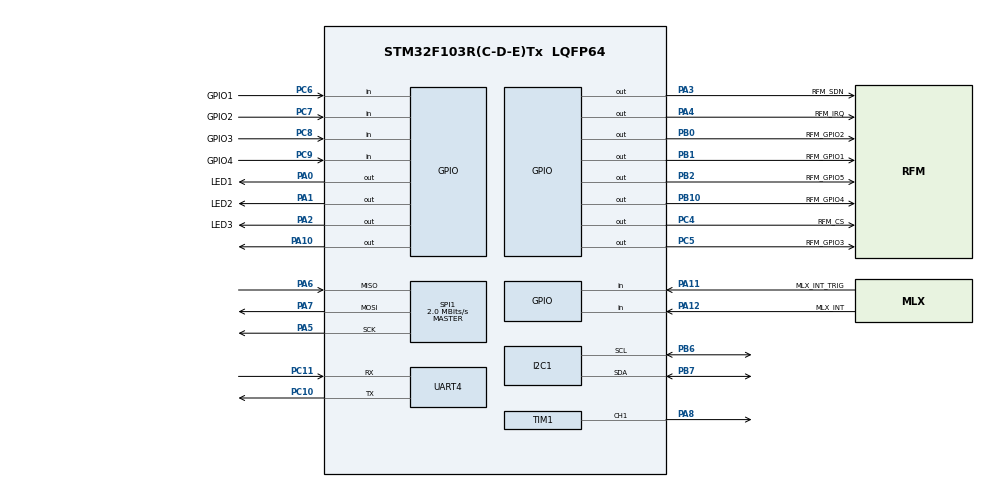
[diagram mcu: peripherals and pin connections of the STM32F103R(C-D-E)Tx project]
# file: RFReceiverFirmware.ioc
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Mcu.Family=STM32F1
Mcu.Name=STM32F103R(C-D-E)Tx
Mcu.Package=LQFP64
NVIC.PriorityGroup=NVIC_PRIORITYGROUP_4
NVIC.TIM2_IRQn=true\:0\:0\:false\:false\:true\:true\:true\:true
NVIC.TIM3_IRQn=true\:0\:0\:false\:false\:true\:true\:true\:true
NVIC.TIM4_IRQn=true\:0\:0\:false\:false\:true\:true\:true\:true
NVIC.TIM5_IRQn=true\:0\:0\:false\:false\:true\:true\:true\:true
PA0-WKUP.GPIO_Label=LED1
PA0-WKUP.Signal=GPIO_Output
PA1.GPIO_Label=LED2
PA1.Signal=GPIO_Output
PA10.Signal=GPIO_Output
PA11.GPIO_Label=MLX_INT_TRIG
PA11.Signal=GPIO_Input
PA12.GPIO_Label=MLX_INT
PA12.Signal=GPIO_Input
PA13.Mode=Trace_Asynchronous_SW
PA13.Signal=SYS_JTMS-SWDIO
PA14.Mode=Trace_Asynchronous_SW
PA14.Signal=SYS_JTCK-SWCLK
PA2.GPIO_Label=LED3
PA2.Signal=GPIO_Output
PA3.GPIO_Label=RFM_SDN
PA3.Signal=GPIO_Output
PA4.GPIO_Label=RFM_IRQ
PA4.Signal=GPIO_Output
PA5.Mode=Full_Duplex_Master
PA5.Signal=SPI1_SCK
PA6.Mode=Full_Duplex_Master
PA6.Signal=SPI1_MISO
PA7.Mode=Full_Duplex_Master
PA7.Signal=SPI1_MOSI
PA8.Signal=S_TIM1_CH1
PB0.GPIO_Label=RFM_GPIO2
PB0.Signal=GPIO_Output
PB1.GPIO_Label=RFM_GPIO1
PB1.Signal=GPIO_Output
PB10.GPIO_Label=RFM_GPIO4
PB10.Signal=GPIO_Output
PB2.GPIO_Label=RFM_GPIO5
PB2.Signal=GPIO_Output
PB3.Mode=Trace_Asynchronous_SW
PB3.Signal=SYS_JTDO-TRACESWO
PB6.Mode=I2C
PB6.Signal=I2C1_SCL
PB7.Mode=I2C
PB7.Signal=I2C1_SDA
PC10.Mode=Asynchronous
PC10.Signal=UART4_TX
PC11.Mode=Asynchronous
PC11.Signal=UART4_RX
PC4.GPIO_Label=RFM_CS
PC4.Signal=GPIO_Output
PC5.GPIO_Label=RFM_GPIO3
PC5.Signal=GPIO_Output
PC6.GPIO_Label=GPIO1
PC6.Signal=GPIO_Input
PC7.GPIO_Label=GPIO2
PC7.Signal=GPIO_Input
PC8.GPIO_Label=GPIO3
PC8.Signal=GPIO_Input
PC9.GPIO_Label=GPIO4
PC9.Signal=GPIO_Input
ProjectManager.HeapSize=0x200
ProjectManager.StackSize=0x400
ProjectManager.TargetToolchain=STM32CubeIDE
RCC.AHBFreq_Value=64000000
RCC.APB1CLKDivider=RCC_HCLK_DIV2
RCC.APB1Freq_Value=32000000
RCC.APB1TimFreq_Value=64000000
RCC.APB2Freq_Value=64000000
RCC.APB2TimFreq_Value=64000000
RCC.HCLKFreq_Value=64000000
RCC.PLLMUL=RCC_PLL_MUL16
RCC.SYSCLKFreq_VALUE=64000000
RCC.SYSCLKSource=RCC_SYSCLKSOURCE_PLLCLK
RCC.USBFreq_Value=64000000
SH.S_TIM1_CH1.0=TIM1_CH1,PWM Generation1 CH1
SPI1.BaudRatePrescaler=SPI_BAUDRATEPRESCALER_32
SPI1.CalculateBaudRate=2.0 MBits/s
SPI1.Direction=SPI_DIRECTION_2LINES
SPI1.Mode=SPI_MODE_MASTER
SPI1.VirtualType=VM_MASTER
TIM1.Channel-PWM\ Generation1\ CH1=TIM_CHANNEL_1
TIM1.Prescaler=900
TIM1.TIM_MasterOutputTrigger=TIM_TRGO_OC1REF
TIM2.Channel-Output\ Compare1\ No\ Output=TIM_CHANNEL_1
TIM2.OCMode_1=TIM_OCMODE_ACTIVE
TIM2.Prescaler=64000
TIM3.Channel-Output\ Compare1\ No\ Output=TIM_CHANNEL_1
TIM3.OCMode_1=TIM_OCMODE_ACTIVE
TIM3.Prescaler=16000
TIM4.Channel-Output\ Compare1\ No\ Output=TIM_CHANNEL_1
TIM4.OCMode_1=TIM_OCMODE_ACTIVE
TIM4.Prescaler=16000
TIM5.Channel-Output\ Compare1\ No\ Output=TIM_CHANNEL_1
TIM5.OCMode_1=TIM_OCMODE_ACTIVE
TIM5.Prescaler=64000
UART4.VirtualMode=Asynchronous
VP_TIM1_VS_ClockSourceINT.Mode=Internal
VP_TIM2_VS_ClockSourceINT.Mode=Internal
VP_TIM2_VS_no_output1.Mode=Output Compare1 No Output
VP_TIM3_VS_ClockSourceINT.Mode=Internal
VP_TIM3_VS_no_output1.Mode=Output Compare1 No Output
VP_TIM4_VS_ClockSourceINT.Mode=Internal
VP_TIM4_VS_no_output1.Mode=Output Compare1 No Output
VP_TIM5_VS_ClockSourceINT.Mode=Internal
VP_TIM5_VS_no_output1.Mode=Output Compare1 No Output
board=custom

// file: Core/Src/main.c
/* USER CODE BEGIN Header */
/**
  ******************************************************************************
  * @file           : main.c
  * @brief          : Main program body
  ******************************************************************************
  * @attention
  *
  * Copyright (c) 2025 STMicroelectronics.
  * All rights reserved.
  *
  * This software is licensed under terms that can be found in the LICENSE file
  * in the root directory of this software component.
  * If no LICENSE file comes with this software, it is provided AS-IS.
  *
  ******************************************************************************
  */
#include "GAUL_drivers/RFM22.h"
#include "GAUL_drivers/Pulse_pin.h"
#include "GAUL_drivers/i2c_lcd.h"
#include "GAUL_drivers/buzzer.h"
#include "stdio.h"
#include <string.h>
/* USER CODE END Header */
#include "main.h"

I2C_HandleTypeDef hi2c1;

SPI_HandleTypeDef hspi1;

TIM_HandleTypeDef htim1;
TIM_HandleTypeDef htim2;
TIM_HandleTypeDef htim3;
TIM_HandleTypeDef htim4;
TIM_HandleTypeDef htim5;

UART_HandleTypeDef huart4;

void SystemClock_Config(void);
static void MX_GPIO_Init(void);
static void MX_I2C1_Init(void);
static void MX_SPI1_Init(void);
static void MX_TIM1_Init(void);
static void MX_TIM2_Init(void);
static void MX_TIM3_Init(void);
static void MX_TIM4_Init(void);
static void MX_TIM5_Init(void);
static void MX_UART4_Init(void);
/* USER CODE BEGIN PFP */
void PUSH_ISR(uint16_t GPIO_pin);
/* USER CODE END PFP */

/* USER CODE BEGIN 0 */

uint8_t rfm22_interrupt_flag = 0;
uint8_t pushbutton_interrupt_flag = 0;
uint8_t pushbutton_pushed[4] = {0};

void HAL_GPIO_EXTI_Callback(uint16_t GPIO_Pin)
{
	if (GPIO_Pin == RFM_IRQ_Pin) rfm22_interrupt_flag = 1;
	if ((GPIO_Pin == GPIO1_Pin) | (GPIO_Pin == GPIO2_Pin) | (GPIO_Pin == GPIO3_Pin) | (GPIO_Pin == GPIO4_Pin)) PUSH_ISR(GPIO_Pin);
}

void PUSH_ISR(uint16_t GPIO_pin)
{
	pushbutton_interrupt_flag = 1;
	pushbutton_pushed[0] |= (GPIO_pin == GPIO1_Pin);
	pushbutton_pushed[1] |= (GPIO_pin == GPIO2_Pin);
	pushbutton_pushed[2] |= (GPIO_pin == GPIO3_Pin);
	pushbutton_pushed[3] |= (GPIO_pin == GPIO4_Pin);

}

void signal_strenght_bar(char *string, int length, float percent)
{
	if (percent > 100) percent = 100;
	int nb_square = percent * length / 100;
	int nb_dash = length - nb_square;

	for (int i = 0; i < nb_square; i++)
	{
		string[i] = '#';
	}
	for (int i = nb_square; i < length; i++)
	{
		string[i] = '-';
	}
}

void print_menu(RFM22 *dev, I2C_LCD_HandleTypeDef *lcd, uint8_t channel, uint8_t rssi, uint8_t ref_rssi, float latitude, float longitude)
{
	char line[20] = {'-'};
	uint32_t freq = RFM22_get_frequency(dev);
	uint16_t MHz = freq /1e6;
	uint16_t kHz = (freq/1000) % 1000;
	uint16_t Hz = freq % 1000;

	float signal_strenght = 100*((float)rssi-(float)ref_rssi)/((float)ref_rssi+1) + 50;

	lcd_clear(lcd);
	lcd_gotoxy(lcd, 0, 0); // ligne 1
	snprintf(line, 21, "CH:%-3u   %3lu.%03lu.%03lu", channel, MHz, kHz, Hz);
	lcd_puts(lcd, line);
	lcd_gotoxy(lcd, 0, 1); // ligne 2
	snprintf(line, 20, "RSSI:%u", rssi);
	lcd_puts(lcd, line);
	lcd_gotoxy(lcd, 0, 2); // ligne 3
	strcpy(line, "GPS");
	lcd_puts(lcd, line);
	lcd_gotoxy(lcd, 0, 3); // ligne 4
	signal_strenght_bar(line, 20, signal_strenght);
	lcd_puts(lcd, line);

}

/* USER CODE END 0 */

int main(void)
{

  /* MCU Configuration--------------------------------------------------------*/

  /* Reset of all peripherals, Initializes the Flash interface and the Systick. */
  HAL_Init();

  /* Configure the system clock */
  SystemClock_Config();

  /* Initialize all configured peripherals */
  MX_GPIO_Init();
  MX_I2C1_Init();
  MX_SPI1_Init();
  MX_TIM1_Init();
  MX_TIM2_Init();
  MX_TIM3_Init();
  MX_TIM4_Init();
  MX_TIM5_Init();
  MX_UART4_Init();
  /* USER CODE BEGIN 2 */
  // init pulsed pins and their respective timers
  Pulse_Pin_Typedef pin1 = PulsePin_init(LED1_GPIO_Port, LED1_Pin, &htim2, TIM_CHANNEL_1);
  Pulse_Pin_Typedef pin2 = PulsePin_init(LED2_GPIO_Port, LED2_Pin, &htim3, TIM_CHANNEL_1);
  Pulse_Pin_Typedef pin3 = PulsePin_init(LED3_GPIO_Port, LED3_Pin, &htim4, TIM_CHANNEL_1);

  // init buzzer and its watch timer
  buzzer_init(&htim1, TIM_CHANNEL_3, &htim5, TIM_CHANNEL_1);

  // init lcd
  I2C_LCD_HandleTypeDef lcd;
  lcd.hi2c = &hi2c1;
  lcd.address = 0x27<<1;
  lcd_init(&lcd);
  lcd_clear(&lcd);

  //init rfm22
  RFM22 rfm22 = {
		  .SPIx = &hspi1,
		  .cs_port = RFM_CS_GPIO_Port,
		  .cs_pin = RFM_CS_Pin,
		  .snd_port = RFM_SDN_GPIO_Port,
		  .snd_pin = RFM_SDN_Pin,
		  .nirq_port = RFM_IRQ_GPIO_Port,
		  .nirq_pin = RFM_IRQ_Pin,
		  .gpio_port_1 = RFM_GPIO1_GPIO_Port,
		  .gpio_pin_1 = RFM_GPIO1_Pin,
		  .gpio_port_2 = RFM_GPIO2_GPIO_Port,
		  .gpio_pin_2 = RFM_GPIO2_Pin,
		  .gpio_port_3 = RFM_GPIO3_GPIO_Port,
		  .gpio_pin_3 = RFM_GPIO3_Pin
  };

  RFM22_init(&rfm22, &rfm22_confs);
  uint8_t channel = 0;
  /* USER CODE END 2 */

  /* Infinite loop */
  /* USER CODE BEGIN WHILE */

  //global vars
  RFM22_channel(&rfm22, channel);
  print_menu(&rfm22, &lcd, 0, 0, 0, 0, 0);
  const char* packet_str = "VE2VQW";
  uint8_t packet[8];
  memcpy(packet,packet_str, 6);    // copy packet_str to packet without '\0'
  uint8_t rssi = 0;
  uint8_t ref_rssi = 0;
  uint32_t freq;
  float latitude = 0;
  float longitude = 0;
  uint8_t spi_rx[1] = {0};

  while (1)
  {
    /* USER CODE END WHILE */

    /* USER CODE BEGIN 3 */

#ifdef TRANSMIT
	  RFM22_transmit(&rfm22, packet, 8);
	  uint32_t tick = HAL_GetTick();
	  while (HAL_GetTick() - tick < 1000);
#endif

#ifdef RECEIVE
	  RFM22_SPI_read(&rfm22, RH_RF22_REG_07_OPERATING_MODE1, spi_rx, 1);
	  if (!(spi_rx[0] & RH_RF22_RXON))
	  {
		  RFM22_rx_mode(&rfm22);
      }
#endif

	  //handle rfm22 interrupts
	  if (rfm22_interrupt_flag || (!HAL_GPIO_ReadPin(RFM_IRQ_GPIO_Port, RFM_IRQ_Pin)))
#ifdef TRANSMIT
	  {
		  rfm22_interrupt_flag = 0;
		  uint8_t interrupts[] = {0, 0};
		  RFM22_SPI_read(&rfm22, RH_RF22_REG_03_INTERRUPT_STATUS1, interrupts, 2);

		  //pk sent interrupt
		  if (interrupts[0] & RH_RF22_IPKSENT)
		  {
			  PulsePin(pin1, 100);
		  }

		  //tx FIFO full
		  if (interrupts[0 & RH_RF22_ITXFFAFULL])
		  {
			  RFM22_clr_tx_FIFO(&rfm22);
		  }
	  }
#endif

#ifdef RECEIVE
	  {
		  rfm22_interrupt_flag = 0;
		  uint8_t interrupts[] = {0, 0};
		  RFM22_SPI_read(&rfm22, RH_RF22_REG_03_INTERRUPT_STATUS1, interrupts, 2);

		  //pk received
		  if (interrupts[0] & RH_RF22_IPKVALID)
		  {
			  PulsePin(pin1, 100);
			  uint8_t lenght = RFM22_available(&rfm22);

			  // GPS routine
			  rssi = RFM22_get_RSSI(&rfm22);
			  RFM22_read_rx(&rfm22, packet, 8);
			  latitude = 0; // à vérifier, supposé transformer en float direct
			  longitude = 0;

			  // rssi routine
			  int16_t rssi_dif = rssi - ref_rssi;
			  freq = 3000 + 200*rssi_dif;
			  buzzer_start(freq, 200);
			  print_menu(&rfm22, &lcd, channel, rssi, ref_rssi, latitude, longitude);
		  }

		  //rx FIFO full
		  if (interrupts[0] & RH_RF22_IRXFFAFULL)
		  {
			  //read last received
			  //RFM22_clr_rx_FIFO(&rfm22);
			  PulsePin(pin3, 100);
		  }

		  //valid preamble
		  if (interrupts[1] & RH_RF22_IPREAVAL)
		  {
		  }

		  //inval preamble
		  if (interrupts[1] & RH_RF22_IPREAINVAL)
		  {
			  PulsePin(pin2, 100);
		  }
	  }

	  if (pushbutton_interrupt_flag)
	  {
		  pushbutton_interrupt_flag = 0;

		  if (pushbutton_pushed[0]) // channel up
		  {
			  channel++;
			  RFM22_channel(&rfm22, channel);
			  print_menu(&rfm22, &lcd, channel, rssi, ref_rssi, latitude, longitude);
		  }
		  if (pushbutton_pushed[1]) // channel down
		  {
			  channel--;
			  RFM22_channel(&rfm22, channel);
			  print_menu(&rfm22, &lcd, channel, rssi, ref_rssi, latitude, longitude);
		  }
		  if (pushbutton_pushed[2]) // zero
		  {
			  ref_rssi = rssi;
		  }
		  if (pushbutton_pushed[3])
		  {

		  }

		  pushbutton_pushed[0] = 0;
		  pushbutton_pushed[1] = 0;
		  pushbutton_pushed[2] = 0;
		  pushbutton_pushed[3] = 0;
	  }
#endif
  }
  /* USER CODE END 3 */
}

void SystemClock_Config(void)
{
  RCC_OscInitTypeDef RCC_OscInitStruct = {0};
  RCC_ClkInitTypeDef RCC_ClkInitStruct = {0};

  /** Initializes the RCC Oscillators according to the specified parameters
  * in the RCC_OscInitTypeDef structure.
  */
  RCC_OscInitStruct.OscillatorType = RCC_OSCILLATORTYPE_HSE;
  RCC_OscInitStruct.HSEState = RCC_HSE_ON;
  RCC_OscInitStruct.HSEPredivValue = RCC_HSE_PREDIV_DIV1;
  RCC_OscInitStruct.HSIState = RCC_HSI_ON;
  RCC_OscInitStruct.PLL.PLLState = RCC_PLL_ON;
  RCC_OscInitStruct.PLL.PLLSource = RCC_PLLSOURCE_HSE;
  RCC_OscInitStruct.PLL.PLLMUL = RCC_PLL_MUL9;
  if (HAL_RCC_OscConfig(&RCC_OscInitStruct) != HAL_OK)
  {
    Error_Handler();
  }

  /** Initializes the CPU, AHB and APB buses clocks
  */
  RCC_ClkInitStruct.ClockType = RCC_CLOCKTYPE_HCLK|RCC_CLOCKTYPE_SYSCLK
                              |RCC_CLOCKTYPE_PCLK1|RCC_CLOCKTYPE_PCLK2;
  RCC_ClkInitStruct.SYSCLKSource = RCC_SYSCLKSOURCE_PLLCLK;
  RCC_ClkInitStruct.AHBCLKDivider = RCC_SYSCLK_DIV1;
  RCC_ClkInitStruct.APB1CLKDivider = RCC_HCLK_DIV2;
  RCC_ClkInitStruct.APB2CLKDivider = RCC_HCLK_DIV1;

  if (HAL_RCC_ClockConfig(&RCC_ClkInitStruct, FLASH_LATENCY_2) != HAL_OK)
  {
    Error_Handler();
  }
}

static void MX_I2C1_Init(void)
{

  hi2c1.Instance = I2C1;
  hi2c1.Init.ClockSpeed = 100000;
  hi2c1.Init.DutyCycle = I2C_DUTYCYCLE_2;
  hi2c1.Init.OwnAddress1 = 0;
  hi2c1.Init.AddressingMode = I2C_ADDRESSINGMODE_7BIT;
  hi2c1.Init.DualAddressMode = I2C_DUALADDRESS_DISABLE;
  hi2c1.Init.OwnAddress2 = 0;
  hi2c1.Init.GeneralCallMode = I2C_GENERALCALL_DISABLE;
  hi2c1.Init.NoStretchMode = I2C_NOSTRETCH_DISABLE;
  if (HAL_I2C_Init(&hi2c1) != HAL_OK)
  {
    Error_Handler();
  }

}

static void MX_SPI1_Init(void)
{

  /* SPI1 parameter configuration*/
  hspi1.Instance = SPI1;
  hspi1.Init.Mode = SPI_MODE_MASTER;
  hspi1.Init.Direction = SPI_DIRECTION_2LINES;
  hspi1.Init.DataSize = SPI_DATASIZE_8BIT;
  hspi1.Init.CLKPolarity = SPI_POLARITY_LOW;
  hspi1.Init.CLKPhase = SPI_PHASE_1EDGE;
  hspi1.Init.NSS = SPI_NSS_SOFT;
  hspi1.Init.BaudRatePrescaler = SPI_BAUDRATEPRESCALER_32;
  hspi1.Init.FirstBit = SPI_FIRSTBIT_MSB;
  hspi1.Init.TIMode = SPI_TIMODE_DISABLE;
  hspi1.Init.CRCCalculation = SPI_CRCCALCULATION_DISABLE;
  hspi1.Init.CRCPolynomial = 10;
  if (HAL_SPI_Init(&hspi1) != HAL_OK)
  {
    Error_Handler();
  }

}

static void MX_TIM1_Init(void)
{

  TIM_ClockConfigTypeDef sClockSourceConfig = {0};
  TIM_MasterConfigTypeDef sMasterConfig = {0};
  TIM_OC_InitTypeDef sConfigOC = {0};
  TIM_BreakDeadTimeConfigTypeDef sBreakDeadTimeConfig = {0};

  htim1.Instance = TIM1;
  htim1.Init.Prescaler = 900;
  htim1.Init.CounterMode = TIM_COUNTERMODE_UP;
  htim1.Init.Period = 65535;
  htim1.Init.ClockDivision = TIM_CLOCKDIVISION_DIV1;
  htim1.Init.RepetitionCounter = 0;
  htim1.Init.AutoReloadPreload = TIM_AUTORELOAD_PRELOAD_DISABLE;
  if (HAL_TIM_Base_Init(&htim1) != HAL_OK)
  {
    Error_Handler();
  }
  sClockSourceConfig.ClockSource = TIM_CLOCKSOURCE_INTERNAL;
  if (HAL_TIM_ConfigClockSource(&htim1, &sClockSourceConfig) != HAL_OK)
  {
    Error_Handler();
  }
  if (HAL_TIM_PWM_Init(&htim1) != HAL_OK)
  {
    Error_Handler();
  }
  sMasterConfig.MasterOutputTrigger = TIM_TRGO_OC1REF;
  sMasterConfig.MasterSlaveMode = TIM_MASTERSLAVEMODE_DISABLE;
  if (HAL_TIMEx_MasterConfigSynchronization(&htim1, &sMasterConfig) != HAL_OK)
  {
    Error_Handler();
  }
  sConfigOC.OCMode = TIM_OCMODE_PWM1;
  sConfigOC.Pulse = 0;
  sConfigOC.OCPolarity = TIM_OCPOLARITY_HIGH;
  sConfigOC.OCNPolarity = TIM_OCNPOLARITY_HIGH;
  sConfigOC.OCFastMode = TIM_OCFAST_DISABLE;
  sConfigOC.OCIdleState = TIM_OCIDLESTATE_RESET;
  sConfigOC.OCNIdleState = TIM_OCNIDLESTATE_RESET;
  if (HAL_TIM_PWM_ConfigChannel(&htim1, &sConfigOC, TIM_CHANNEL_3) != HAL_OK)
  {
    Error_Handler();
  }
  sBreakDeadTimeConfig.OffStateRunMode = TIM_OSSR_DISABLE;
  sBreakDeadTimeConfig.OffStateIDLEMode = TIM_OSSI_DISABLE;
  sBreakDeadTimeConfig.LockLevel = TIM_LOCKLEVEL_OFF;
  sBreakDeadTimeConfig.DeadTime = 0;
  sBreakDeadTimeConfig.BreakState = TIM_BREAK_DISABLE;
  sBreakDeadTimeConfig.BreakPolarity = TIM_BREAKPOLARITY_HIGH;
  sBreakDeadTimeConfig.AutomaticOutput = TIM_AUTOMATICOUTPUT_DISABLE;
  if (HAL_TIMEx_ConfigBreakDeadTime(&htim1, &sBreakDeadTimeConfig) != HAL_OK)
  {
    Error_Handler();
  }
  HAL_TIM_MspPostInit(&htim1);

}

static void MX_TIM2_Init(void)
{

  TIM_ClockConfigTypeDef sClockSourceConfig = {0};
  TIM_MasterConfigTypeDef sMasterConfig = {0};
  TIM_OC_InitTypeDef sConfigOC = {0};

  htim2.Instance = TIM2;
  htim2.Init.Prescaler = 64000;
  htim2.Init.CounterMode = TIM_COUNTERMODE_UP;
  htim2.Init.Period = 65535;
  htim2.Init.ClockDivision = TIM_CLOCKDIVISION_DIV1;
  htim2.Init.AutoReloadPreload = TIM_AUTORELOAD_PRELOAD_DISABLE;
  if (HAL_TIM_Base_Init(&htim2) != HAL_OK)
  {
    Error_Handler();
  }
  sClockSourceConfig.ClockSource = TIM_CLOCKSOURCE_INTERNAL;
  if (HAL_TIM_ConfigClockSource(&htim2, &sClockSourceConfig) != HAL_OK)
  {
    Error_Handler();
  }
  if (HAL_TIM_OC_Init(&htim2) != HAL_OK)
  {
    Error_Handler();
  }
  sMasterConfig.MasterOutputTrigger = TIM_TRGO_RESET;
  sMasterConfig.MasterSlaveMode = TIM_MASTERSLAVEMODE_DISABLE;
  if (HAL_TIMEx_MasterConfigSynchronization(&htim2, &sMasterConfig) != HAL_OK)
  {
    Error_Handler();
  }
  sConfigOC.OCMode = TIM_OCMODE_ACTIVE;
  sConfigOC.Pulse = 0;
  sConfigOC.OCPolarity = TIM_OCPOLARITY_HIGH;
  sConfigOC.OCFastMode = TIM_OCFAST_DISABLE;
  if (HAL_TIM_OC_ConfigChannel(&htim2, &sConfigOC, TIM_CHANNEL_1) != HAL_OK)
  {
    Error_Handler();
  }

}

static void MX_TIM3_Init(void)
{

  TIM_ClockConfigTypeDef sClockSourceConfig = {0};
  TIM_MasterConfigTypeDef sMasterConfig = {0};
  TIM_OC_InitTypeDef sConfigOC = {0};

  htim3.Instance = TIM3;
  htim3.Init.Prescaler = 16000;
  htim3.Init.CounterMode = TIM_COUNTERMODE_UP;
  htim3.Init.Period = 65535;
  htim3.Init.ClockDivision = TIM_CLOCKDIVISION_DIV1;
  htim3.Init.AutoReloadPreload = TIM_AUTORELOAD_PRELOAD_DISABLE;
  if (HAL_TIM_Base_Init(&htim3) != HAL_OK)
  {
    Error_Handler();
  }
  sClockSourceConfig.ClockSource = TIM_CLOCKSOURCE_INTERNAL;
  if (HAL_TIM_ConfigClockSource(&htim3, &sClockSourceConfig) != HAL_OK)
  {
    Error_Handler();
  }
  if (HAL_TIM_OC_Init(&htim3) != HAL_OK)
  {
    Error_Handler();
  }
  sMasterConfig.MasterOutputTrigger = TIM_TRGO_RESET;
  sMasterConfig.MasterSlaveMode = TIM_MASTERSLAVEMODE_DISABLE;
  if (HAL_TIMEx_MasterConfigSynchronization(&htim3, &sMasterConfig) != HAL_OK)
  {
    Error_Handler();
  }
  sConfigOC.OCMode = TIM_OCMODE_ACTIVE;
  sConfigOC.Pulse = 0;
  sConfigOC.OCPolarity = TIM_OCPOLARITY_HIGH;
  sConfigOC.OCFastMode = TIM_OCFAST_DISABLE;
  if (HAL_TIM_OC_ConfigChannel(&htim3, &sConfigOC, TIM_CHANNEL_1) != HAL_OK)
  {
    Error_Handler();
  }

}

static void MX_TIM4_Init(void)
{

  TIM_ClockConfigTypeDef sClockSourceConfig = {0};
  TIM_MasterConfigTypeDef sMasterConfig = {0};
  TIM_OC_InitTypeDef sConfigOC = {0};

  htim4.Instance = TIM4;
  htim4.Init.Prescaler = 16000;
  htim4.Init.CounterMode = TIM_COUNTERMODE_UP;
  htim4.Init.Period = 65535;
  htim4.Init.ClockDivision = TIM_CLOCKDIVISION_DIV1;
  htim4.Init.AutoReloadPreload = TIM_AUTORELOAD_PRELOAD_DISABLE;
  if (HAL_TIM_Base_Init(&htim4) != HAL_OK)
  {
    Error_Handler();
  }
  sClockSourceConfig.ClockSource = TIM_CLOCKSOURCE_INTERNAL;
  if (HAL_TIM_ConfigClockSource(&htim4, &sClockSourceConfig) != HAL_OK)
  {
    Error_Handler();
  }
  if (HAL_TIM_OC_Init(&htim4) != HAL_OK)
  {
    Error_Handler();
  }
  sMasterConfig.MasterOutputTrigger = TIM_TRGO_RESET;
  sMasterConfig.MasterSlaveMode = TIM_MASTERSLAVEMODE_DISABLE;
  if (HAL_TIMEx_MasterConfigSynchronization(&htim4, &sMasterConfig) != HAL_OK)
  {
    Error_Handler();
  }
  sConfigOC.OCMode = TIM_OCMODE_ACTIVE;
  sConfigOC.Pulse = 0;
  sConfigOC.OCPolarity = TIM_OCPOLARITY_HIGH;
  sConfigOC.OCFastMode = TIM_OCFAST_DISABLE;
  if (HAL_TIM_OC_ConfigChannel(&htim4, &sConfigOC, TIM_CHANNEL_1) != HAL_OK)
  {
    Error_Handler();
  }

}

static void MX_TIM5_Init(void)
{

  TIM_ClockConfigTypeDef sClockSourceConfig = {0};
  TIM_MasterConfigTypeDef sMasterConfig = {0};
  TIM_OC_InitTypeDef sConfigOC = {0};

  htim5.Instance = TIM5;
  htim5.Init.Prescaler = 64000;
  htim5.Init.CounterMode = TIM_COUNTERMODE_UP;
  htim5.Init.Period = 65535;
  htim5.Init.ClockDivision = TIM_CLOCKDIVISION_DIV1;
  htim5.Init.AutoReloadPreload = TIM_AUTORELOAD_PRELOAD_DISABLE;
  if (HAL_TIM_Base_Init(&htim5) != HAL_OK)
  {
    Error_Handler();
  }
  sClockSourceConfig.ClockSource = TIM_CLOCKSOURCE_INTERNAL;
  if (HAL_TIM_ConfigClockSource(&htim5, &sClockSourceConfig) != HAL_OK)
  {
    Error_Handler();
  }
  if (HAL_TIM_OC_Init(&htim5) != HAL_OK)
  {
    Error_Handler();
  }
  sMasterConfig.MasterOutputTrigger = TIM_TRGO_RESET;
  sMasterConfig.MasterSlaveMode = TIM_MASTERSLAVEMODE_DISABLE;
  if (HAL_TIMEx_MasterConfigSynchronization(&htim5, &sMasterConfig) != HAL_OK)
  {
    Error_Handler();
  }
  sConfigOC.OCMode = TIM_OCMODE_ACTIVE;
  sConfigOC.Pulse = 0;
  sConfigOC.OCPolarity = TIM_OCPOLARITY_HIGH;
  sConfigOC.OCFastMode = TIM_OCFAST_DISABLE;
  if (HAL_TIM_OC_ConfigChannel(&htim5, &sConfigOC, TIM_CHANNEL_1) != HAL_OK)
  {
    Error_Handler();
  }

}

static void MX_UART4_Init(void)
{

  huart4.Instance = UART4;
  huart4.Init.BaudRate = 115200;
  huart4.Init.WordLength = UART_WORDLENGTH_8B;
  huart4.Init.StopBits = UART_STOPBITS_1;
  huart4.Init.Parity = UART_PARITY_NONE;
  huart4.Init.Mode = UART_MODE_TX_RX;
  huart4.Init.HwFlowCtl = UART_HWCONTROL_NONE;
  huart4.Init.OverSampling = UART_OVERSAMPLING_16;
  if (HAL_UART_Init(&huart4) != HAL_OK)
  {
    Error_Handler();
  }

}

static void MX_GPIO_Init(void)
{
  GPIO_InitTypeDef GPIO_InitStruct = {0};

  /* GPIO Ports Clock Enable */
  __HAL_RCC_GPIOD_CLK_ENABLE();
  __HAL_RCC_GPIOA_CLK_ENABLE();
  __HAL_RCC_GPIOC_CLK_ENABLE();
  __HAL_RCC_GPIOB_CLK_ENABLE();

  /*Configure GPIO pin Output Level */
  HAL_GPIO_WritePin(GPIOA, LED1_Pin|LED2_Pin|LED3_Pin|RFM_SDN_Pin, GPIO_PIN_RESET);

  /*Configure GPIO pin Output Level */
  HAL_GPIO_WritePin(GPIOC, RFM_CS_Pin|RFM_GPIO3_Pin, GPIO_PIN_RESET);

  /*Configure GPIO pin Output Level */
  HAL_GPIO_WritePin(GPIOB, RFM_GPIO2_Pin|RFM_GPIO1_Pin|RFM_GPIO5_Pin|RFM_GPIO4_Pin, GPIO_PIN_RESET);

  /*Configure GPIO pins : LED1_Pin LED2_Pin LED3_Pin RFM_SDN_Pin */
  GPIO_InitStruct.Pin = LED1_Pin|LED2_Pin|LED3_Pin|RFM_SDN_Pin;
  GPIO_InitStruct.Mode = GPIO_MODE_OUTPUT_PP;
  GPIO_InitStruct.Pull = GPIO_NOPULL;
  GPIO_InitStruct.Speed = GPIO_SPEED_FREQ_LOW;
  HAL_GPIO_Init(GPIOA, &GPIO_InitStruct);

  /*Configure GPIO pin : RFM_IRQ_Pin */
  GPIO_InitStruct.Pin = RFM_IRQ_Pin;
  GPIO_InitStruct.Mode = GPIO_MODE_IT_RISING;
  GPIO_InitStruct.Pull = GPIO_NOPULL;
  HAL_GPIO_Init(RFM_IRQ_GPIO_Port, &GPIO_InitStruct);

  /*Configure GPIO pins : RFM_CS_Pin RFM_GPIO3_Pin */
  GPIO_InitStruct.Pin = RFM_CS_Pin|RFM_GPIO3_Pin;
  GPIO_InitStruct.Mode = GPIO_MODE_OUTPUT_PP;
  GPIO_InitStruct.Pull = GPIO_NOPULL;
  GPIO_InitStruct.Speed = GPIO_SPEED_FREQ_LOW;
  HAL_GPIO_Init(GPIOC, &GPIO_InitStruct);

  /*Configure GPIO pins : RFM_GPIO2_Pin RFM_GPIO1_Pin RFM_GPIO5_Pin RFM_GPIO4_Pin */
  GPIO_InitStruct.Pin = RFM_GPIO2_Pin|RFM_GPIO1_Pin|RFM_GPIO5_Pin|RFM_GPIO4_Pin;
  GPIO_InitStruct.Mode = GPIO_MODE_OUTPUT_PP;
  GPIO_InitStruct.Pull = GPIO_NOPULL;
  GPIO_InitStruct.Speed = GPIO_SPEED_FREQ_LOW;
  HAL_GPIO_Init(GPIOB, &GPIO_InitStruct);

  /*Configure GPIO pins : GPIO1_Pin GPIO2_Pin GPIO3_Pin GPIO4_Pin */
  GPIO_InitStruct.Pin = GPIO1_Pin|GPIO2_Pin|GPIO3_Pin|GPIO4_Pin;
  GPIO_InitStruct.Mode = GPIO_MODE_IT_RISING;
  GPIO_InitStruct.Pull = GPIO_NOPULL;
  HAL_GPIO_Init(GPIOC, &GPIO_InitStruct);

  /*Configure GPIO pins : MLX_INT_TRIG_Pin MLX_INT_Pin */
  GPIO_InitStruct.Pin = MLX_INT_TRIG_Pin|MLX_INT_Pin;
  GPIO_InitStruct.Mode = GPIO_MODE_INPUT;
  GPIO_InitStruct.Pull = GPIO_NOPULL;
  HAL_GPIO_Init(GPIOA, &GPIO_InitStruct);

  /* EXTI interrupt init*/
  HAL_NVIC_SetPriority(EXTI4_IRQn, 0, 0);
  HAL_NVIC_EnableIRQ(EXTI4_IRQn);

  HAL_NVIC_SetPriority(EXTI9_5_IRQn, 0, 0);
  HAL_NVIC_EnableIRQ(EXTI9_5_IRQn);

}

void Error_Handler(void)
{
  __disable_irq();
  while (1)
  {
  }
}
